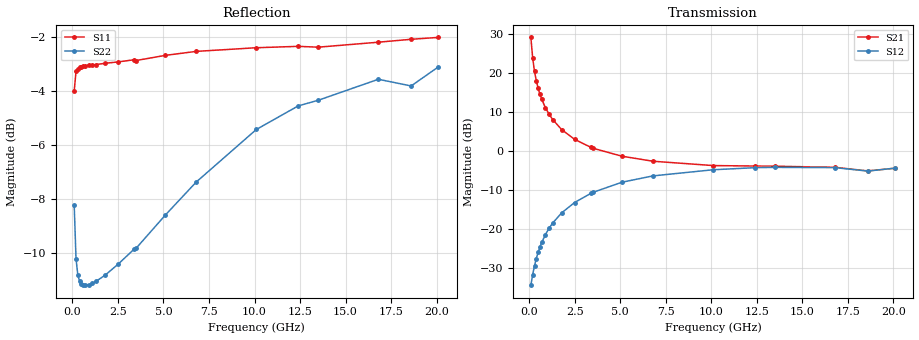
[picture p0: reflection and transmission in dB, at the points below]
!  Infineon Technologies AG
! BFR380L3 , PF131585-7, No.6, Th 09.10.01, soldered on pcb-board, measured with PP GSG850
!  Vce=1.0 V,  Ic=80.0 mA
! Common Emitter S-Parameters:  15. November 2001
#  GHz  S  MA  R  50
! f  S11  S21  S12  S22
! GHz  Mag  Ang  Mag  Ang  Mag  Ang  Mag  Ang
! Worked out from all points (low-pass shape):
!   201 points, 100 MHz to 20.1 GHz, reference 50 ohm
!   highest |S21| = 29.06 dB at 100 MHz (marker M1); lowest = -5.2 dB at 18.6 GHz (marker M2)
!   |S21| within 3 dB of the highest: start of sweep to 156.1 MHz
!   lowest |S11| = -4.0 dB at 100 MHz (marker M3), VSWR 4.42, Z = 12.2 - j13.9 ohm
!   |S11| at or under -10 dB: nowhere
!   |S22| runs from -11.2 to -3.1 dB; largest |S21 - S12| = 28
!   S11 on the Smith chart (normalised r, x): 100 MHz: 0.24, -0.28; 900 MHz: 0.18, +0.08; 3.4 GHz: 0.19, +0.42; 6.8 GHz: 0.26, +0.87; 12.4 GHz: 0.50, +1.59; 20.1 GHz: 1.04, +2.64
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0.1  0.6307 -147.3  28.38 114.8  0.01899 53.7  0.3873 -102.6
0.2  0.6854 -164.9  15.33 100.3  0.02596 56.1  0.3084 -134.7
0.3  0.6938 -172.3  10.41 94.2  0.03369 61.7  0.2872 -149.1
0.4  0.6977 -176.7  7.867 90.1  0.04161 64.9  0.2801 -157.3
0.5  0.6993 180.0  6.317 87.0  0.05014 67.4  0.2771 -162.5
0.6  0.7014 177.2  5.285 84.4  0.05874 68.7  0.276 -166.3
0.7  0.7023 174.9  4.546 81.9  0.06721 69.5  0.2756 -169.1
0.9  0.7033 170.8  3.559 77.7  0.08454 70.0  0.276 -173.4
1.1  0.7044 167.1  2.94 73.8  0.1017 69.7  0.2778 -176.5
1.3  0.7057 163.6  2.508 70.1  0.1188 68.9  0.2801 -179.1
1.8  0.7096 155.6  1.859 61.5  0.1609 66.1  0.2876 175.7
2.5  0.7137 145.1  1.402 50.8  0.2172 60.9  0.3011 169.5
3.4  0.7203 132.7  1.105 39.0  0.2853 53.7  0.3215 161.8
3.5  0.718 131.3  1.08 37.7  0.2927 52.8  0.3225 161.3
5.1  0.7339 112.4  0.8518 21.5  0.3954 39.6  0.3714 147.8
6.8  0.7465 95.5  0.7346 9.3  0.4765 26.8  0.4277 133.0
10.1  0.7582 72.2  0.6465 -6.8  0.5712 5.0  0.5351 108.8
12.4  0.7627 60.7  0.6375 -16.4  0.6071 -8.5  0.5917 92.7
13.5  0.76 56.1  0.6339 -21.0  0.6131 -14.5  0.6061 86.3
16.8  0.7763 45.4  0.6144 -32.3  0.608 -28.8  0.6628 68.9
18.6  0.786 42.5  0.5517 -38.0  0.5496 -35.3  0.6442 65.1
20.1  0.7924 36.8  0.5988 -43.4  0.5988 -41.3  0.6989 55.0
